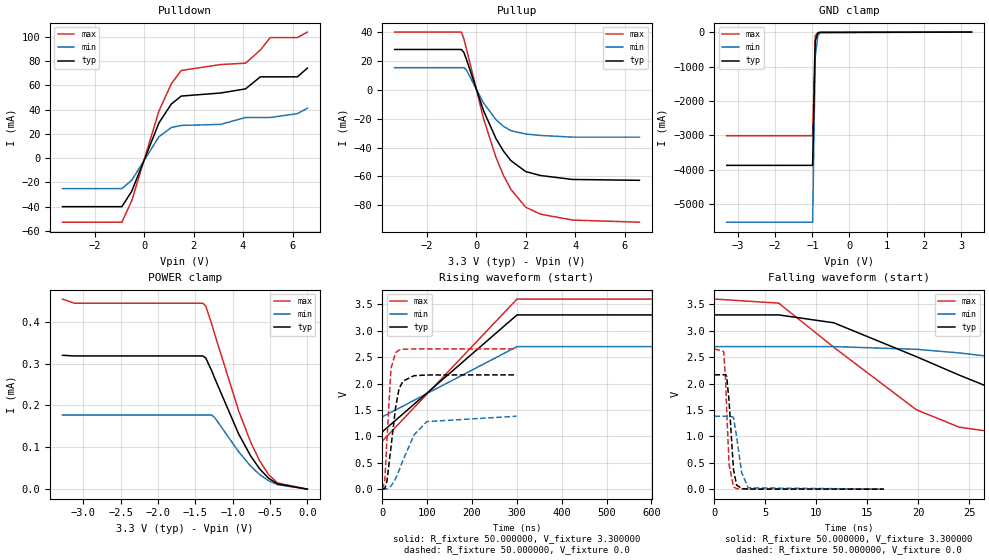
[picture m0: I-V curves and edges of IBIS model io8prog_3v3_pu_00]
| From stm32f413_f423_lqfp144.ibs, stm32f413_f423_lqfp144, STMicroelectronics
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|   Model io8prog_3v3_pu_00
[Model]  io8prog_3v3_pu_00
Model_type I/O
Polarity   Non-Inverting
Enable   Active-Low
Vinl =   0.990000V
Vinh =   2.310000V
Vmeas =  1.650000V
Cref =   100.000000pF
Rref =   1.000000k
Vref =   3.300000V
C_comp   2.665600pF   2.506300pF   2.859000pF
[Temperature Range]   25.000000   0.125000k   -40.000000
[Pullup Reference]   3.300000V   2.700000V   3.600000V
[Pulldown Reference]   0.0V   0.0V   0.0V
[POWER Clamp Reference]   3.300000V   2.700000V   3.600000V
[GND Clamp Reference]   0.0V   0.0V   0.0V
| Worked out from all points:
|   slope of the pulldown table from 0 to 0.495 V, typ, clamps not added: 20 ohm
|   slope of the pullup table from 0 to 0.495 V, typ, clamps not added: 21.7 ohm
|   GND clamp passes 1 mA (typ) near -0.57 V on its own axis
|   rising waveform, R_fixture 50.000000, V_fixture 3.300000: 20-80 % time 180ns typ, 180ns min, 180ns max; typ from 1.09 V to 3.3 V
|   rising waveform, R_fixture 50.000000, V_fixture 0.0: 20-80 % time 18.3ns typ, 43.4ns min, 9.75ns max; typ from 0.001 V to 2.17 V
|   falling waveform, R_fixture 50.000000, V_fixture 3.300000: 20-80 % time 17.4ns typ, 34.6ns min, 10.8ns max; typ from 3.3 V to 1.09 V
|   falling waveform, R_fixture 50.000000, V_fixture 0.0: 20-80 % time 421ps typ, 611ps min, 335ps max; typ from 2.17 V to 0.001 V
[Pulldown]
|Voltage   I(typ)   I(min)   I(max)
-3.3V     -40.11mA   -25.24mA   -52.93mA
-900mV    -40.11mA   -25.24mA   -52.93mA
-500mV    -27.39mA   -18.31mA   -35.21mA
600mV     29.01mA    17.61mA    38.88mA
1.1V      44.56mA    25.16mA    61.26mA
1.5V      51.11mA    26.89mA    72.21mA
3.1V      53.67mA    27.79mA    77.15mA
4.1V      57.05mA    33.46mA    78.24mA
4.7V      66.98mA    33.46mA    89.07mA
5.1V      66.98mA    33.46mA    99.37mA
6.2V      66.99mA    36.63mA    99.37mA
6.6V      74.18mA    41.08mA    103.9mA
[Pullup]
|Voltage   I(typ)   I(min)   I(max)
-3.3V     27.92mA    15.29mA    39.95mA
-600mV    27.92mA    15.29mA    39.95mA
-500mV    25.88mA    15.29mA    35.28mA
-400mV    21.3mA     13.82mA    28.75mA
300mV     -14.62mA   -9.248mA   -20.15mA
800mV     -33.8mA    -20.67mA   -46.89mA
1.1V      -42.41mA   -25.28mA   -59.19mA
1.4V      -49.01mA   -28.29mA   -68.91mA
2V        -56.64mA   -30.64mA   -81.32mA
2.6V      -59.37mA   -31.63mA   -86.15mA
3.9V      -62.11mA   -32.8mA    -90.25mA
6.6V      -62.7mA    -32.8mA    -91.7mA
[GND_clamp]
|Voltage   I(typ)   I(min)   I(max)
-3.3V     -3.872A    -5.523A    -3.009A
-990mV    -3.872A    -5.523A    -3.009A
-920mV    -262.2mA   -719.6mA   -104.3mA
-850mV    -25.19mA   -100.9mA   -13.07mA
-780mV    -6.959mA   -18mA      -7.19mA
3.28V     0A         5.62nA     0A
[POWER_clamp]
|Voltage   I(typ)   I(min)   I(max)
-3.28V    320uA      177.1uA    454.4uA
-3.12V    318.4uA    177.1uA    444.4uA
-1.4V     318.4uA    177.1uA    444.4uA
-1.36V    313.4uA    177.1uA    437.3uA
-1.28V    282.4uA    177.1uA    394.1uA
-1.24V    264.6uA    170.9uA    369.7uA
-920mV    131.9uA    89.37uA    187.2uA
-760mV    79.48uA    55.14uA    112.7uA
-640mV    48.78uA    35.05uA    68.06uA
-520mV    26.21uA    20.12uA    35uA
-400mV    12.52uA    10.82uA    14.88uA
0V        0A         12.39nA    0A
[Ramp]
| variable   typ   min   max
dV/dt_r  1.29849/18.27012n   0.82877/43.32612n   1.59326/9.74120n
dV/dt_f  1.32696/17.43805n   0.79824/35.61691n   1.61360/10.82772n
R_load = 50.000000
[Rising Waveform]
R_fixture= 50.000000
V_fixture= 3.300000
V_fixture_min= 2.700000
V_fixture_max= 3.600000
|time   V(typ)   V(min)   V(max)
0s        1.088V     1.37V      910.7mV
300.3ns   3.3V       2.7V       3.6V
600.6ns   3.3V       2.7V       3.6V
29.73us   3.3V       2.7V       3.6V
[Rising Waveform]
R_fixture= 50.000000
V_fixture= 0.0
V_fixture_min= 0.0
V_fixture_max= 0.0
|time   V(typ)   V(min)   V(max)
0s        1.044mV    1.019mV    1.073mV
5.405ns   12.66mV    2.791mV    154mV
10.21ns   151.7mV    5.184mV    935.5mV
19.22ns   795.3mV    57.37mV    2.285V
29.43ns   1.543V     199.1mV    2.587V
37.24ns   1.903V     355mV      2.632V
46.25ns   2.049V     553.5mV    2.649V
70.87ns   2.149V     1.031V     2.656V
99.1ns    2.163V     1.28V      2.656V
299.1ns   2.165V     1.382V     2.656V
[Falling Waveform]
R_fixture= 50.000000
V_fixture= 3.300000
V_fixture_min= 2.700000
V_fixture_max= 3.600000
|time   V(typ)   V(min)   V(max)
0s        3.3V       2.7V       3.6V
6.306ns   3.3V       2.7V       3.523V
11.71ns   3.151V     2.7V       2.687V
19.82ns   2.509V     2.649V     1.503V
24.02ns   2.16V      2.58V      1.175V
28.23ns   1.832V     2.487V     1.06V
34.53ns   1.464V     2.326V     988.8mV
42.04ns   1.277V     2.121V     953.2mV
70.27ns   1.124V     1.58V      916mV
149.5ns   1.088V     1.37V      910.7mV
[Falling Waveform]
R_fixture= 50.000000
V_fixture= 0.0
V_fixture_min= 0.0
V_fixture_max= 0.0
|time   V(typ)   V(min)   V(max)
0s        2.165V     1.382V     2.656V
900.9ps   2.166V     1.382V     2.608V
1.101ns   2.172V     1.382V     2.047V
1.201ns   2.132V     1.382V     1.487V
1.435ns   1.668V     1.383V     470mV
1.869ns   373.7mV    1.361V     42.08mV
2.169ns   80.98mV    1.003V     11.83mV
2.669ns   10.38mV    317.8mV    5.631mV
3.303ns   3.347mV    26.8mV     5.272mV
16.62ns   1.044mV    1.019mV    1.073mV
